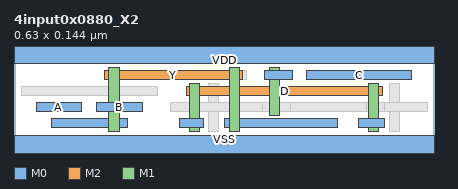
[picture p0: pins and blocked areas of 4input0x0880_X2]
MACRO 4input0x0880_X2
  CLASS CORE ;
  ORIGIN 0 0 ;
  FOREIGN 4input0x0880_X2 0 0 ;
  SIZE 0.6300 BY 0.1440 ;
  SYMMETRY X Y ;
  SITE coresite ;
  PIN A
    DIRECTION INPUT ;
    USE SIGNAL ;
    PORT
      LAYER M0 ;
        RECT 0.0330 0.0530 0.1020 0.0670 ;
    END
  END A
  PIN B
    DIRECTION INPUT ;
    USE SIGNAL ;
    PORT
      LAYER M0 ;
        RECT 0.1230 0.0530 0.1920 0.0670 ;
    END
  END B
  PIN C
    DIRECTION INPUT ;
    USE SIGNAL ;
    PORT
      LAYER M0 ;
        RECT 0.4380 0.1010 0.5970 0.1150 ;
    END
  END C
  PIN D
    DIRECTION INPUT ;
    USE SIGNAL ;
    PORT
      LAYER M2 ;
        RECT 0.2580 0.0770 0.5520 0.0910 ;
      LAYER M1 ;
        RECT 0.2625 0.0240 0.2775 0.0960 ;
        RECT 0.3825 0.0480 0.3975 0.1200 ;
        RECT 0.5325 0.0240 0.5475 0.0960 ;
      LAYER M0 ;
        RECT 0.5175 0.0290 0.5550 0.0430 ;
        RECT 0.3750 0.1010 0.4170 0.1150 ;
        RECT 0.2475 0.0290 0.2850 0.0430 ;
    END
  END D
  PIN Y
    DIRECTION OUTPUT ;
    USE SIGNAL ;
    PORT
      LAYER M2 ;
        RECT 0.1350 0.1010 0.3420 0.1150 ;
      LAYER M1 ;
        RECT 0.1425 0.0240 0.1575 0.1200 ;
        RECT 0.3225 0.0240 0.3375 0.1200 ;
      LAYER M0 ;
        RECT 0.3150 0.0290 0.4845 0.0430 ;
        RECT 0.0555 0.0290 0.1695 0.0430 ;
    END
  END Y
  PIN VDD
    DIRECTION INOUT ;
    USE POWER ;
    SHAPE ABUTMENT ;
    PORT
      LAYER M0 ;
        RECT 0.0000 0.1260 0.6300 0.1620 ;
    END
  END VDD
  PIN VSS
    DIRECTION INOUT ;
    USE GROUND ;
    SHAPE ABUTMENT ;
    PORT
      LAYER M0 ;
        RECT 0.0000 -0.0180 0.6300 0.0180 ;
    END
  END VSS
  OBS
    LAYER V1 ;
      RECT 0.2930 0.0530 0.3070 0.0670 ;
      RECT 0.5630 0.0530 0.5770 0.0670 ;
      RECT 0.1430 0.1010 0.1570 0.1150 ;
      RECT 0.3230 0.1010 0.3370 0.1150 ;
      RECT 0.2630 0.0770 0.2770 0.0910 ;
      RECT 0.3830 0.0770 0.3970 0.0910 ;
      RECT 0.5330 0.0770 0.5470 0.0910 ;
    LAYER M2 ;
      RECT 0.2880 0.0530 0.5850 0.0670 ;
    LAYER V0 ;
      RECT 0.2930 0.0530 0.3070 0.0670 ;
      RECT 0.5630 0.0530 0.5770 0.0670 ;
      RECT 0.1430 0.0290 0.1570 0.0430 ;
      RECT 0.3230 0.0290 0.3370 0.0430 ;
      RECT 0.2630 0.0290 0.2770 0.0430 ;
      RECT 0.3830 0.1010 0.3970 0.1150 ;
      RECT 0.5330 0.0290 0.5470 0.0430 ;
    LAYER M1 ;
      RECT 0.2925 0.0240 0.3075 0.0960 ;
      RECT 0.5625 0.0240 0.5775 0.0960 ;
    LAYER M0 ;
      RECT 0.2355 0.0530 0.3720 0.0670 ;
      RECT 0.4155 0.0530 0.5295 0.0670 ;
      RECT 0.5550 0.0530 0.6195 0.0670 ;
      RECT 0.0105 0.0770 0.2145 0.0910 ;
      RECT 0.2805 0.0770 0.4845 0.0910 ;
      RECT 0.1455 0.1010 0.3495 0.1150 ;
  END
END 4input0x0880_X2
